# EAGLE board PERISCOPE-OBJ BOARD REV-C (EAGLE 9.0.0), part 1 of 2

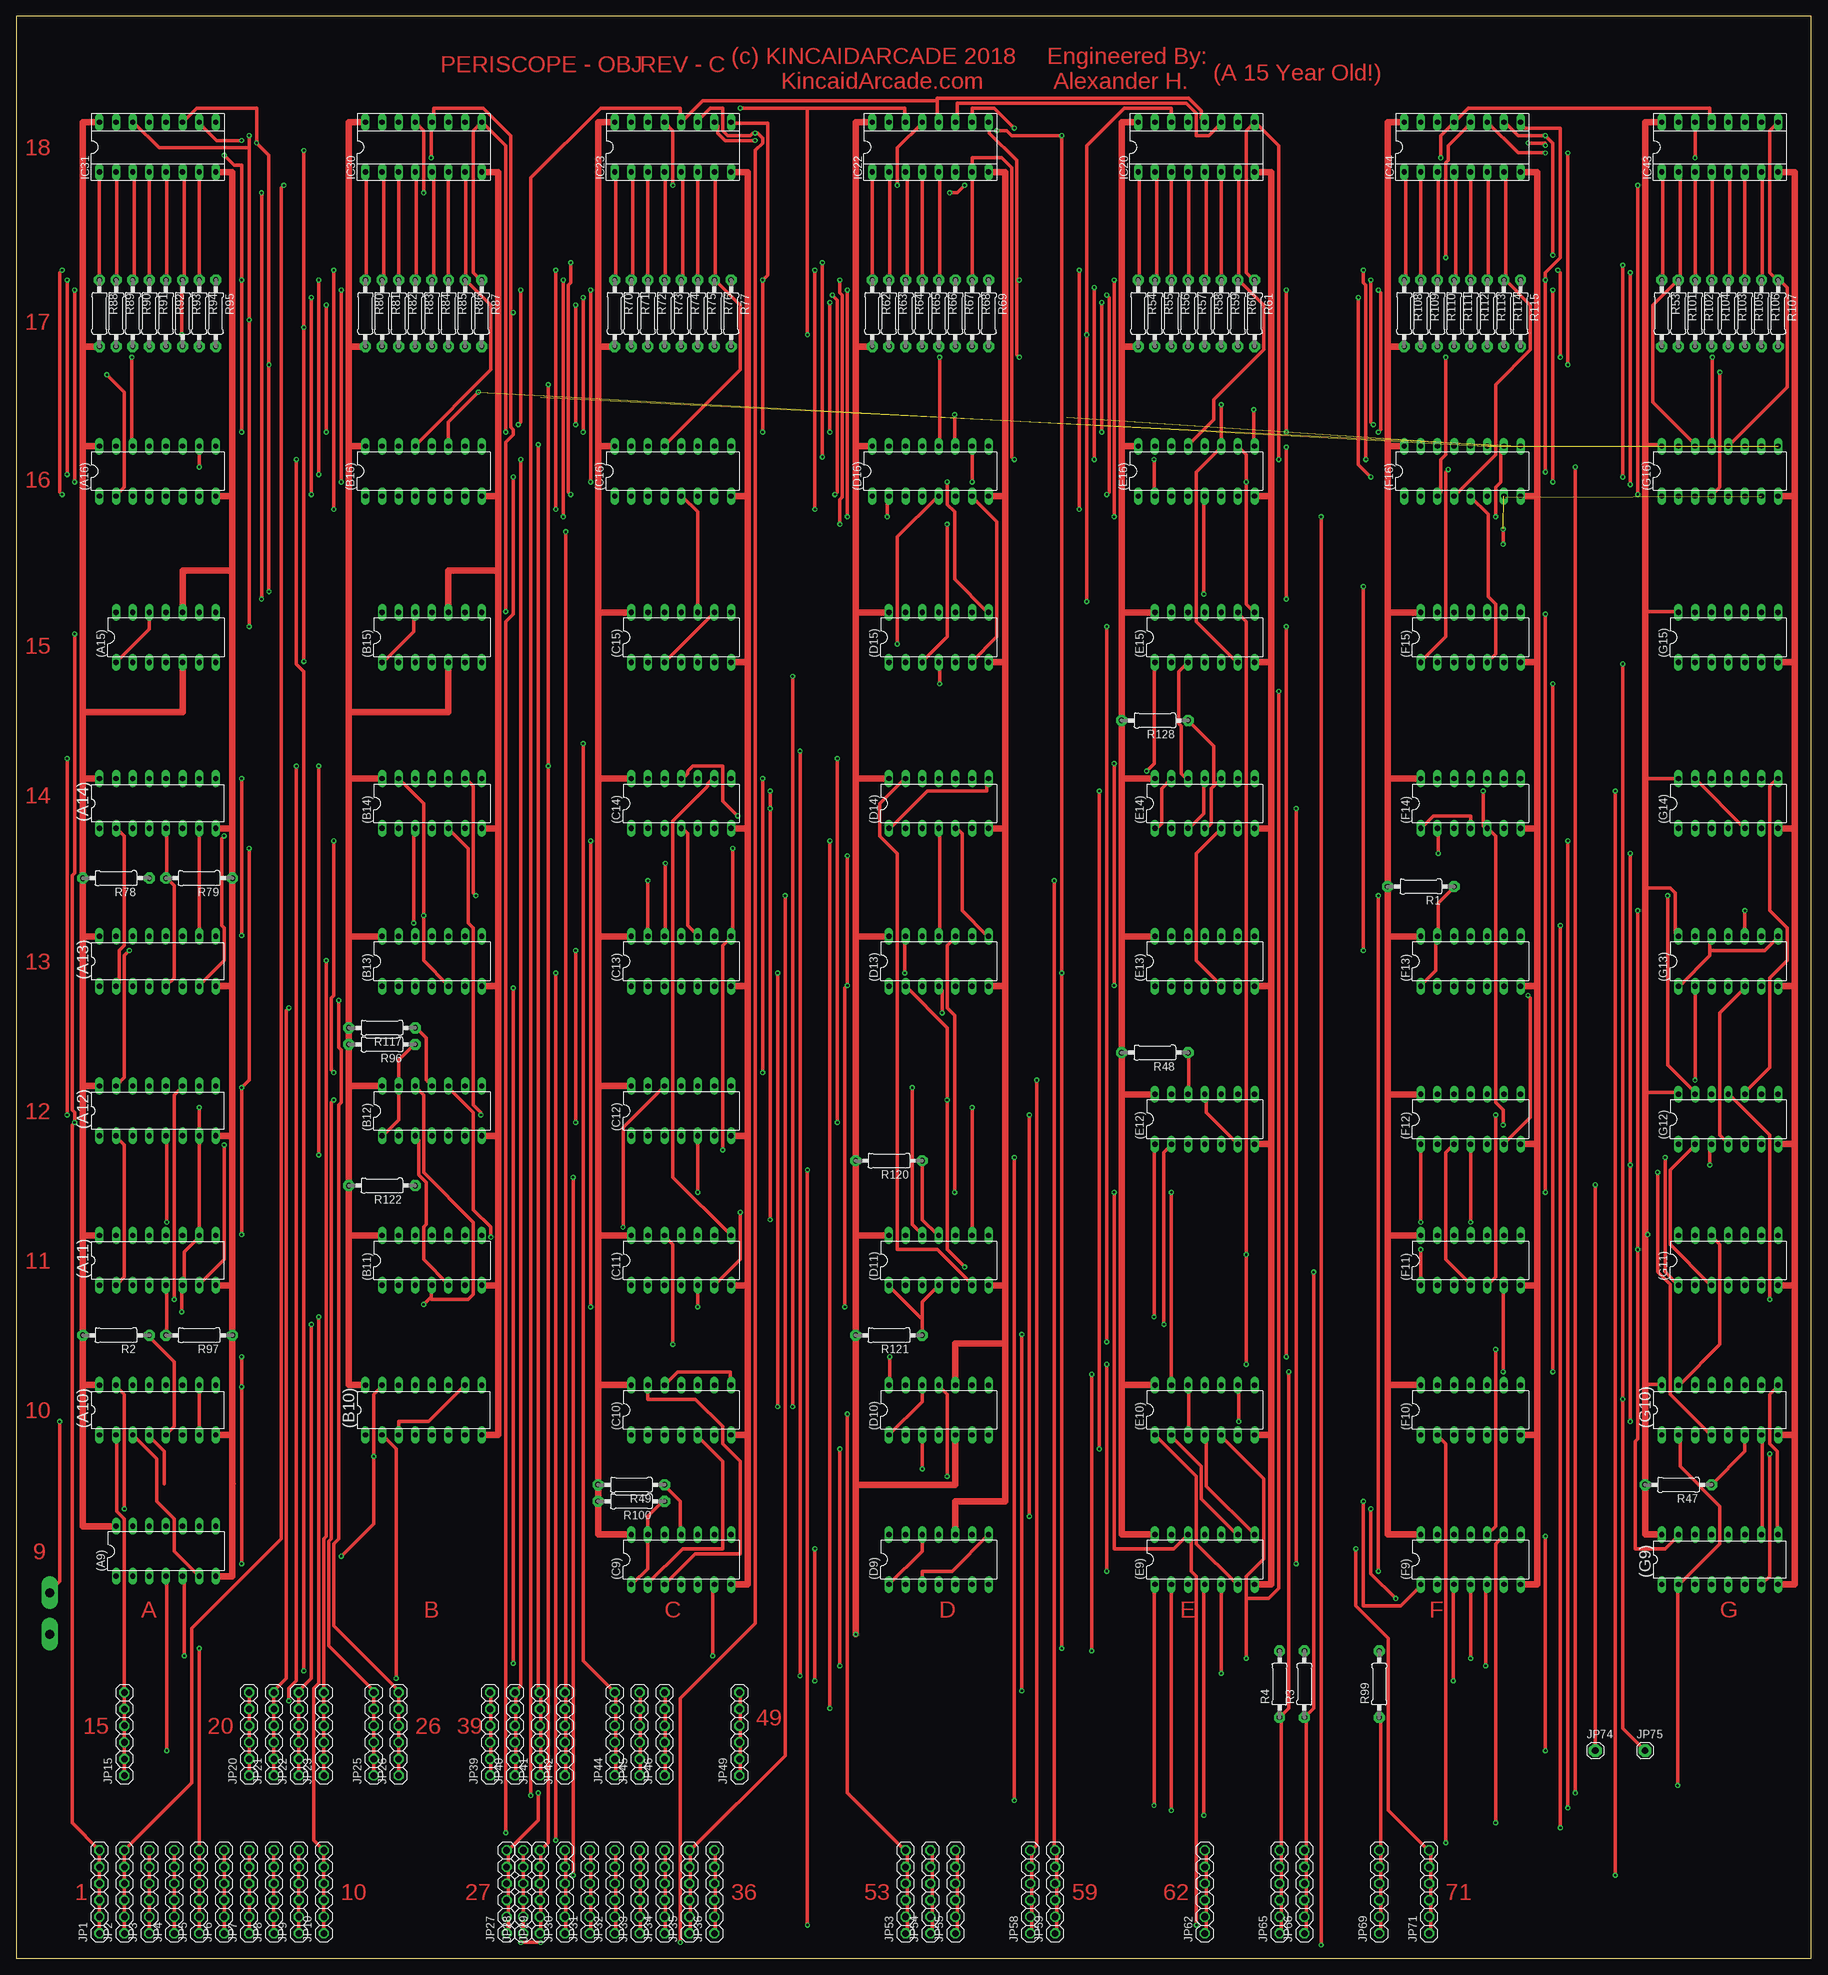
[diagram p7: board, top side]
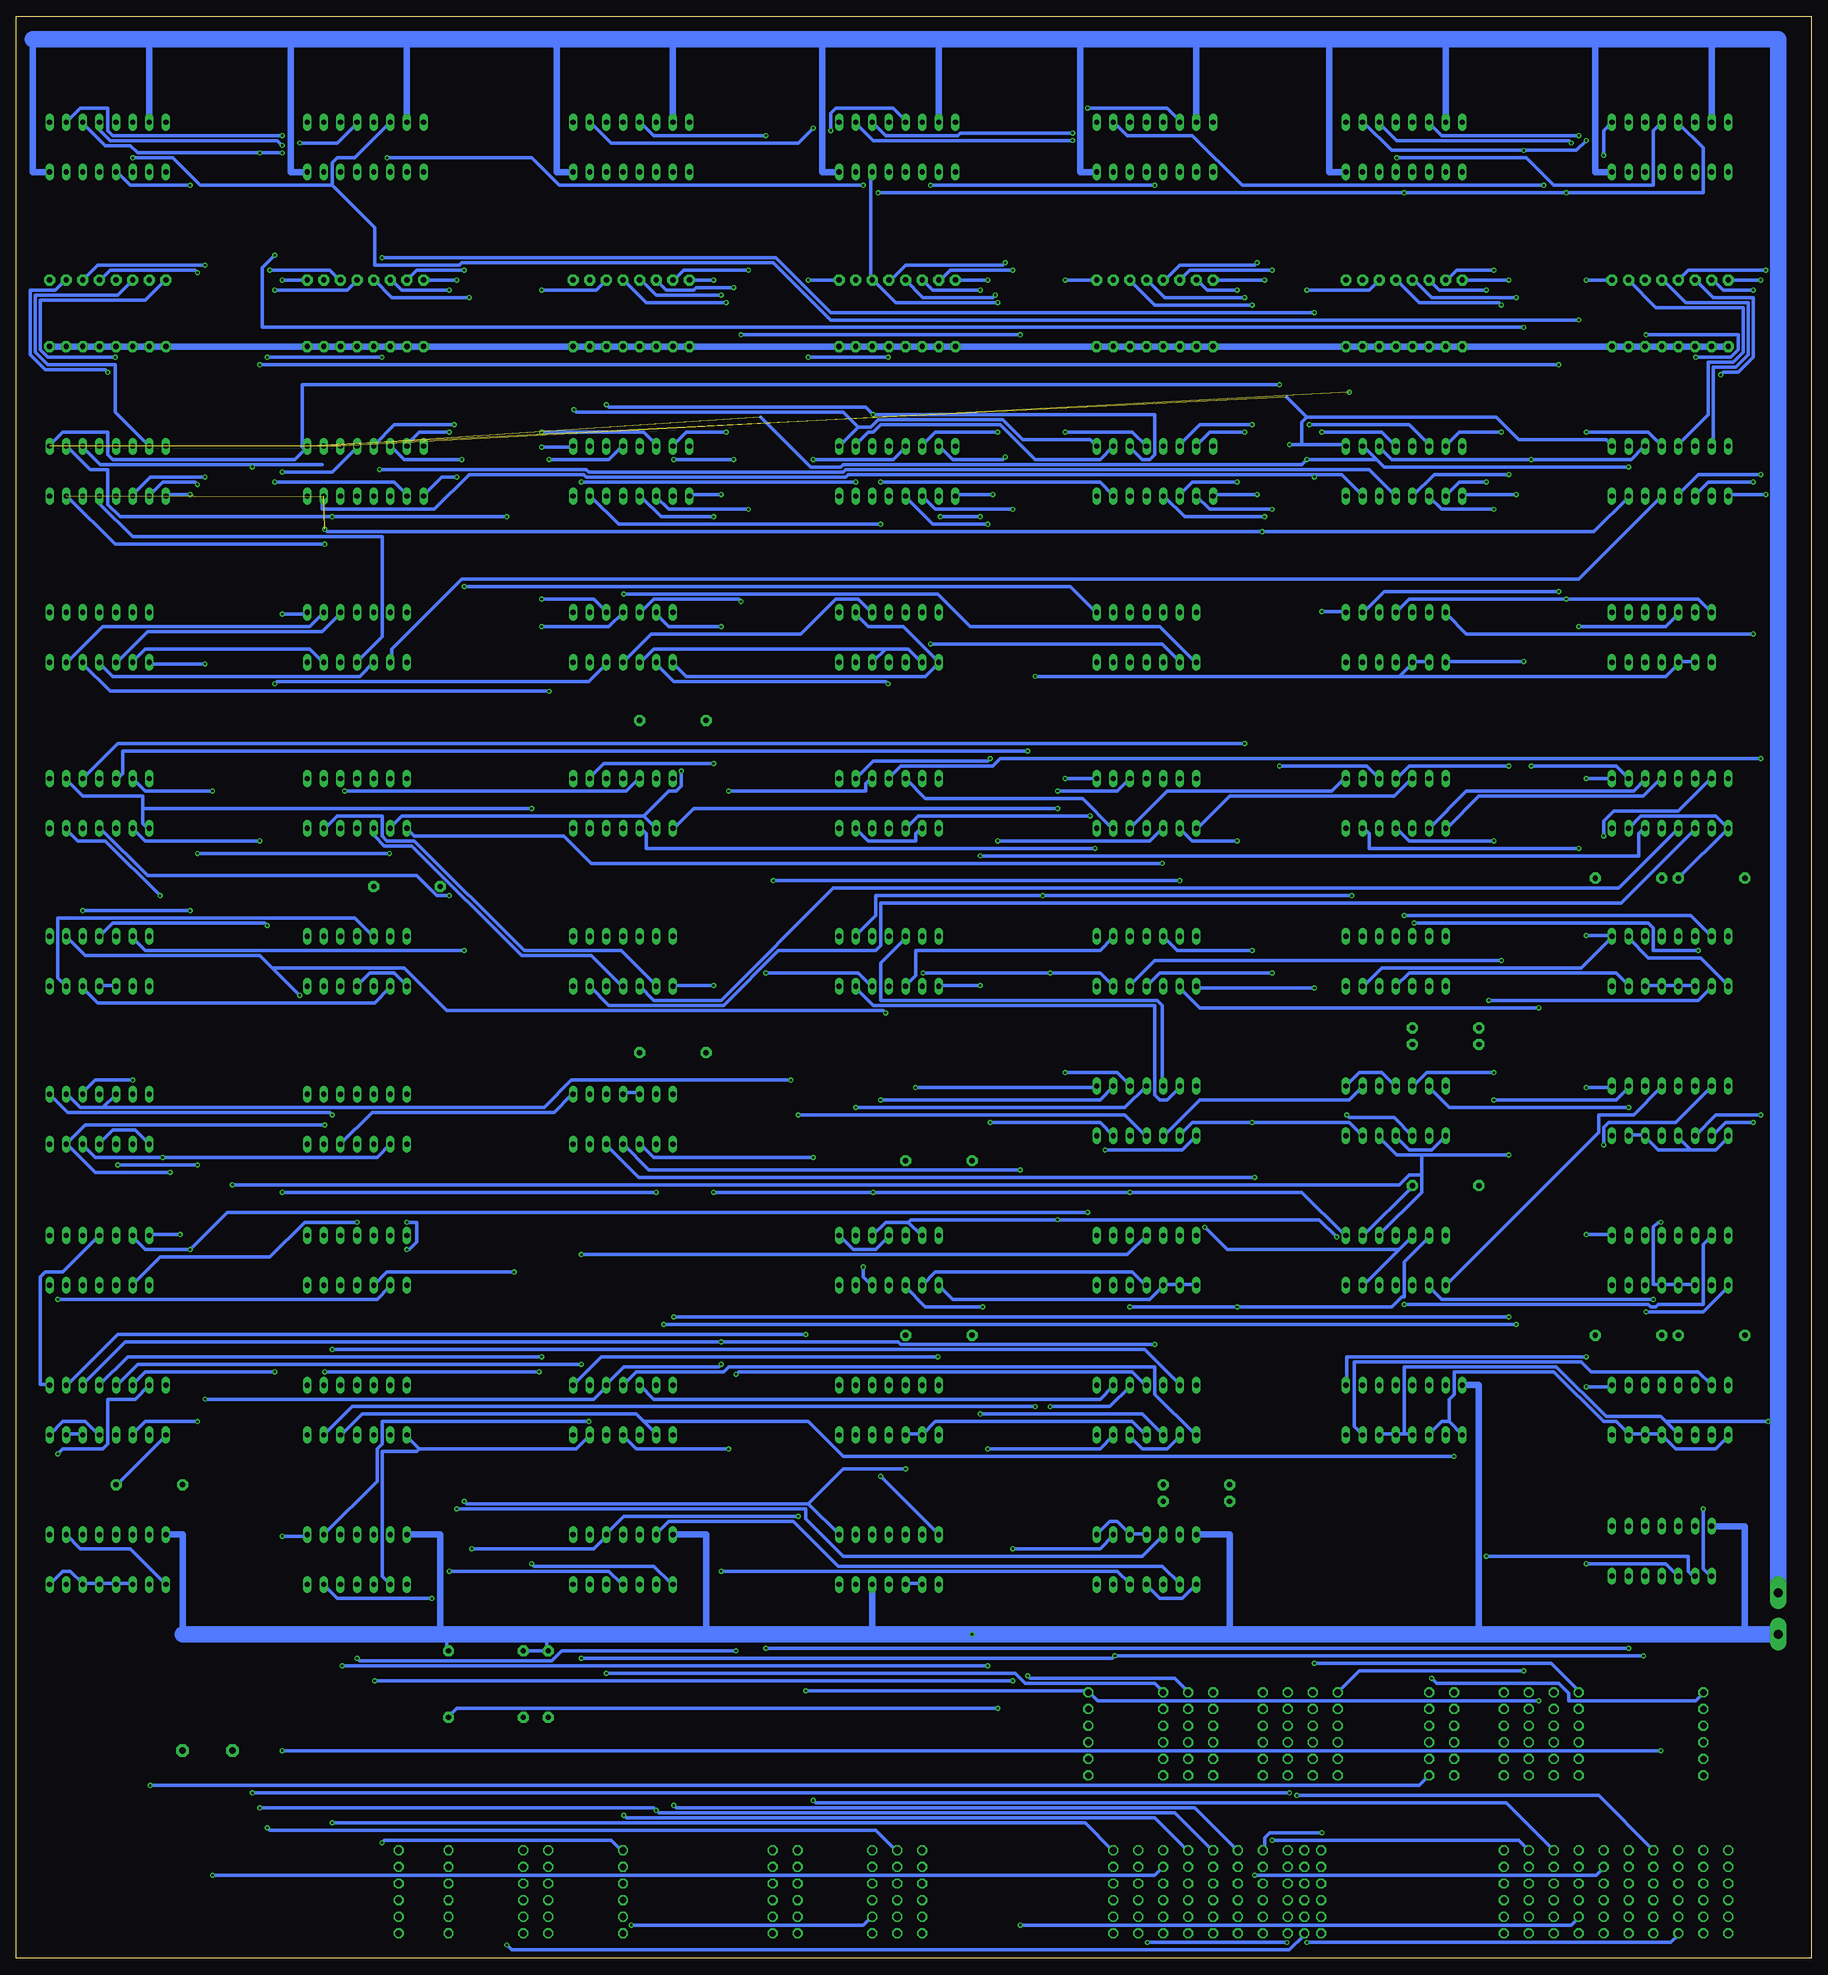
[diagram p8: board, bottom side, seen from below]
Size 274.3 x 296.85 mm. Coordinates in mm from the lower left corner, seen from the top.
Outline: 0,0 274.3,0 274.3,296.85 0,296.85 0,0
Copper layers (1*16): Top 0.035mm / dielectric 1.5mm / Bottom 0.035mm
Design rules "default": minimum track width 6mil, minimum drill 0.35mm, track to track 6mil, track to pad 6mil, pad to pad 6mil, via to via 6mil, smd to smd 6mil, copper to edge 40mil, drill to drill 6mil, minimum pad ring 10mil, minimum via ring 8mil, stop-mask expansion 4mil, vias tented up to drill 0mil, thermal gap 10mil
Net classes: 0 default: width 0.508 mm, clearance 0.254 mm

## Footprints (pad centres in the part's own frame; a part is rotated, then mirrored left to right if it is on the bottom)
DIL14 = drill 0.813 long: 1 -7.62,-3.81; 2 -5.08,-3.81; 3 -2.54,-3.81; 4 0,-3.81; 5 2.54,-3.81; 6 5.08,-3.81; 7 7.62,-3.81; 8 7.62,3.81; 9 5.08,3.81; 10 2.54,3.81; 11 0,3.81; 12 -2.54,3.81; 13 -5.08,3.81; 14 -7.62,3.81
DIL16 = drill 0.813 long: 1 -8.89,-3.81; 2 -6.35,-3.81; 3 -3.81,-3.81; 4 -1.27,-3.81; 5 1.27,-3.81; 6 3.81,-3.81; 7 6.35,-3.81; 8 8.89,-3.81; 9 8.89,3.81; 10 6.35,3.81; 11 3.81,3.81; 12 1.27,3.81; 13 -1.27,3.81; 14 -3.81,3.81; 15 -6.35,3.81; 16 -8.89,3.81
SOCKET-16 = drill 0.813 long: 1 -8.89,-3.81; 2 -6.35,-3.81; 3 -3.81,-3.81; 4 -1.27,-3.81; 5 1.27,-3.81; 6 3.81,-3.81; 7 6.35,-3.81; 8 8.89,-3.81; 9 8.89,3.81; 10 6.35,3.81; 11 3.81,3.81; 12 1.27,3.81; 13 -1.27,3.81; 14 -3.81,3.81; 15 -6.35,3.81; 16 -8.89,3.81
1X06 = drill 1.016 octagon: 1 -6.35,0; 2 -3.81,0; 3 -1.27,0; 4 1.27,0; 5 3.81,0; 6 6.35,0
1X1-BIGPOGO = drill 1.4 pad 2.54 long: P$1 0,0
1X01 = drill 1.016 pad 1.93 octagon: 1 0,0
0207/10 = drill 0.813 pad 1.676 octagon: 1 -5.08,0; 2 5.08,0

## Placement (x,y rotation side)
(A9)  7400N  [DIL14]  22.86,62.23 0 top
(A10)  74161N  [DIL16]  21.59,83.82 0 top
(A11)  74161N  [DIL16]  21.59,106.68 0 top
(A12)  74161N  [DIL16]  21.59,129.54 0 top
(A13)  74161N  [DIL16]  21.59,152.4 0 top
(A14)  74161N  [DIL16]  21.59,176.53 0 top
(A15)  74LS93N  [DIL14]  22.86,201.93 0 top
(A16)  74151N  [DIL16]  21.59,227.33 0 top
(B10)  74161N  [DIL16]  62.23,83.82 0 top
(B11)  74LS21N  [DIL14]  63.5,106.68 0 top
(B12)  74107N  [DIL14]  63.5,129.54 0 top
(B13)  7400N  [DIL14]  63.5,152.4 0 top
(B14)  7410N  [DIL14]  63.5,176.53 0 top
(B15)  74LS93N  [DIL14]  63.5,201.93 0 top
(B16)  74151N  [DIL16]  62.23,227.33 0 top
(C9)  74107N  [DIL14]  101.6,60.96 0 top
(C10)  74S08N  [DIL14]  101.6,83.82 0 top
(C11)  7430N  [DIL14]  101.6,106.68 0 top
(C12)  74S08N  [DIL14]  101.6,129.54 0 top
(C13)  74LS21N  [DIL14]  101.6,152.4 0 top
(C14)  7404N  [DIL14]  101.6,176.53 0 top
(C15)  7432N  [DIL14]  101.6,201.93 0 top
(C16)  74151N  [DIL16]  100.33,227.33 0 top
(D9)  74LS93N  [DIL14]  140.97,60.96 0 top
(D10)  74LS93N  [DIL14]  140.97,83.82 0 top
(D11)  74107N  [DIL14]  140.97,106.68 0 top
(D13)  74S08N  [DIL14]  140.97,152.4 0 top
(D14)  7432N  [DIL14]  140.97,176.53 0 top
(D15)  7400N  [DIL14]  140.97,201.93 0 top
(D16)  74151N  [DIL16]  139.7,227.33 0 top
(E9)  74LS21N  [DIL14]  181.61,60.96 0 top
(E10)  74S08N  [DIL14]  181.61,83.82 0 top
(E12)  7430N  [DIL14]  181.61,128.27 0 top
(E13)  7432N  [DIL14]  181.61,152.4 0 top
(E14)  74S74N  [DIL14]  181.61,176.53 0 top
(E15)  7404N  [DIL14]  181.61,201.93 0 top
(E16)  74151N  [DIL16]  180.34,227.33 0 top
(F9)  7432N  [DIL14]  222.25,60.96 0 top
(F10)  7404N  [DIL14]  222.25,83.82 0 top
(F11)  7402N  [DIL14]  222.25,106.68 0 top
(F12)  7404N  [DIL14]  222.25,128.27 0 top
(F13)  74107N  [DIL14]  222.25,152.4 0 top
(F14)  74S08N  [DIL14]  222.25,176.53 0 top
(F15)  7432N  [DIL14]  222.25,201.93 0 top
(F16)  74151N  [DIL16]  220.98,227.33 0 top
(G9)  74161N  [DIL16]  260.35,60.96 0 top
(G10)  74161N  [DIL16]  260.35,83.82 0 top
(G11)  7400N  [DIL14]  261.62,106.68 0 top
(G12)  7432N  [DIL14]  261.62,128.27 0 top
(G13)  74S08N  [DIL14]  261.62,152.4 0 top
(G14)  74LS21N  [DIL14]  261.62,176.53 0 top
(G15)  74S08N  [DIL14]  261.62,201.93 0 top
(G16)  74151N  [DIL16]  260.35,227.33 0 top
IC20  82S23 #5  [SOCKET-16]  180.34,276.86 0 top
IC22  82S23 #4  [SOCKET-16]  139.7,276.86 0 top
IC23  82S23 #3  [SOCKET-16]  100.33,276.86 0 top
IC30  82S23 #2  [SOCKET-16]  62.23,276.86 0 top
IC31  82S23 #1  [SOCKET-16]  21.59,276.86 0 top
IC43  82S23 #7  [SOCKET-16]  260.35,276.86 0 top
IC44  82S23 #6  [SOCKET-16]  220.98,276.86 0 top
JP1  [1X06]  12.7,10.16 90 top
JP2  [1X06]  16.51,10.16 90 top
JP3  [1X06]  20.32,10.16 90 top
JP4  [1X06]  24.13,10.16 90 top
JP5  [1X06]  27.94,10.16 90 top
JP6  [1X06]  31.75,10.16 90 top
JP7  [1X06]  35.56,10.16 90 top
JP8  [1X06]  39.37,10.16 90 top
JP9  [1X06]  43.18,10.16 90 top
JP10  [1X06]  46.99,10.16 90 top
JP15  [1X06]  16.51,34.29 90 top
JP20  [1X06]  35.56,34.29 90 top
JP21  [1X06]  39.37,34.29 90 top
JP22  [1X06]  43.18,34.29 90 top
JP23  [1X06]  46.99,34.29 90 top
JP25  [1X06]  54.61,34.29 90 top
JP26  [1X06]  58.42,34.29 90 top
JP27  [1X06]  74.93,10.16 90 top
JP28  [1X06]  77.47,10.16 90 top
JP29  [1X06]  80.01,10.16 90 top
JP30  [1X06]  83.82,10.16 90 top
JP31  [1X06]  87.63,10.16 90 top
JP32  [1X06]  91.44,10.16 90 top
JP33  [1X06]  95.25,10.16 90 top
JP34  [1X06]  99.06,10.16 90 top
JP35  [1X06]  102.87,10.16 90 top
JP36  [1X06]  106.68,10.16 90 top
JP39  [1X06]  72.39,34.29 90 top
JP40  [1X06]  76.2,34.29 90 top
JP41  [1X06]  80.01,34.29 90 top
JP42  [1X06]  83.82,34.29 90 top
JP44  [1X06]  91.44,34.29 90 top
JP45  [1X06]  95.25,34.29 90 top
JP46  [1X06]  99.06,34.29 90 top
JP49  [1X06]  110.49,34.29 90 top
JP53  [1X06]  135.89,10.16 90 top
JP54  [1X06]  139.7,10.16 90 top
JP55  [1X06]  143.51,10.16 90 top
JP58  [1X06]  154.94,10.16 90 top
JP59  [1X06]  158.75,10.16 90 top
JP62  [1X06]  181.61,10.16 90 top
JP65  [1X06]  193.04,10.16 90 top
JP66  [1X06]  196.85,10.16 90 top
JP69  [1X06]  208.28,10.16 90 top
JP71  [1X06]  215.9,10.16 90 top
JP72  [1X1-BIGPOGO]  5.08,49.53 90 top
JP73  [1X1-BIGPOGO]  5.08,55.88 90 top
JP74  [1X01]  241.3,31.75 0 top
JP75  [1X01]  248.92,31.75 0 top
R1  1K  [0207/10]  214.63,163.83 180 top
R2  1K  [0207/10]  15.24,95.25 180 top
R3  1K  [0207/10]  196.85,41.91 90 top
R4  1K  [0207/10]  193.04,41.91 90 top
R47  1K  [0207/10]  254,72.39 180 top
R48  1K  [0207/10]  173.99,138.43 180 top
R49  1K  [0207/10]  93.98,72.39 180 top
R53  1K  [0207/10]  251.46,251.46 270 top
R54  1K  [0207/10]  171.45,251.46 270 top
R55  1K  [0207/10]  173.99,251.46 270 top
R56  1K  [0207/10]  176.53,251.46 270 top
R57  1K  [0207/10]  179.07,251.46 270 top
R58  1K  [0207/10]  181.61,251.46 270 top
R59  1K  [0207/10]  184.15,251.46 270 top
R60  1K  [0207/10]  186.69,251.46 270 top
R61  1K  [0207/10]  189.23,251.46 270 top
R62  1K  [0207/10]  130.81,251.46 270 top
R63  1K  [0207/10]  133.35,251.46 270 top
R64  1K  [0207/10]  135.89,251.46 270 top
R65  1K  [0207/10]  138.43,251.46 270 top
R66  1K  [0207/10]  140.97,251.46 270 top
R67  1K  [0207/10]  143.51,251.46 270 top
R68  1K  [0207/10]  146.05,251.46 270 top
R69  1K  [0207/10]  148.59,251.46 270 top
R70  1K  [0207/10]  91.44,251.46 270 top
R71  1K  [0207/10]  93.98,251.46 270 top
R72  1K  [0207/10]  96.52,251.46 270 top
R73  1K  [0207/10]  99.06,251.46 270 top
R74  1K  [0207/10]  101.6,251.46 270 top
R75  1K  [0207/10]  104.14,251.46 270 top
R76  1K  [0207/10]  106.68,251.46 270 top
R77  1K  [0207/10]  109.22,251.46 270 top
R78  1K  [0207/10]  15.24,165.1 180 top
R79  1K  [0207/10]  27.94,165.1 180 top
R80  1K  [0207/10]  53.34,251.46 270 top
R81  1K  [0207/10]  55.88,251.46 270 top
R82  1K  [0207/10]  58.42,251.46 270 top
R83  1K  [0207/10]  60.96,251.46 270 top
R84  1K  [0207/10]  63.5,251.46 270 top
R85  1K  [0207/10]  66.04,251.46 270 top
R86  1K  [0207/10]  68.58,251.46 270 top
R87  1K  [0207/10]  71.12,251.46 270 top
R88  1K  [0207/10]  12.7,251.46 270 top
R89  1K  [0207/10]  15.24,251.46 270 top
R90  1K  [0207/10]  17.78,251.46 270 top
R91  1K  [0207/10]  20.32,251.46 270 top
R92  1K  [0207/10]  22.86,251.46 270 top
R93  1K  [0207/10]  25.4,251.46 270 top
R94  1K  [0207/10]  27.94,251.46 270 top
R95  1K  [0207/10]  30.48,251.46 270 top
R96  1K  [0207/10]  55.88,139.7 180 top
R97  1K  [0207/10]  27.94,95.25 180 top
R99  1K  [0207/10]  208.28,41.91 90 top
R100  1K  [0207/10]  93.98,69.85 180 top
R101  1K  [0207/10]  254,251.46 270 top
R102  1K  [0207/10]  256.54,251.46 270 top
R103  1K  [0207/10]  261.62,251.46 270 top
R104  1K  [0207/10]  259.08,251.46 270 top
R105  1K  [0207/10]  264.16,251.46 270 top
R106  1K  [0207/10]  266.7,251.46 270 top
R107  1K  [0207/10]  269.24,251.46 270 top
R108  1K  [0207/10]  212.09,251.46 270 top
R109  1K  [0207/10]  214.63,251.46 270 top
R110  1K  [0207/10]  217.17,251.46 270 top
R111  1K  [0207/10]  219.71,251.46 270 top
R112  1K  [0207/10]  222.25,251.46 270 top
R113  1K  [0207/10]  224.79,251.46 270 top
R114  1K  [0207/10]  227.33,251.46 270 top
R115  1K  [0207/10]  229.87,251.46 270 top
R117  1K  [0207/10]  55.88,142.24 180 top
R120  1K  [0207/10]  133.35,121.92 180 top
R121  1K  [0207/10]  133.35,95.25 180 top
R122  1K  [0207/10]  55.88,118.11 180 top
R128  1K  [0207/10]  173.99,189.23 180 top

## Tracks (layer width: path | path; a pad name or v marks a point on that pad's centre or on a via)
1H  (via drill 0.35)
  Top 0.508: JP2.1 JP2.2 JP2.3 JP2.4 JP2.5 JP2.6 26.8,26.8 26.8,50.42 40.51,64.13 40.51,270.64 v40.89,271.02 | IC23.10 107.19,280.16 107.19,279.02 108.33,277.88 v112.9,277.88 | v152.53,279.78 149.48,282.83 146.05,282.83 IC22.10
  Bottom 0.508: v112.9,277.88 143.38,277.88 146.05,280.54 IC22.10 | v152.53,279.78 154.81,277.5 183.39,277.5 186.44,280.54 IC20.10 | v40.89,271.02 87,271.02 94.62,278.64 104.52,278.64 106.43,280.54 IC23.10
1V  (via drill 0.35)
  Top 0.508: JP27.1 75.18,3.94 75.18,6.22 JP27.2 75.18,6.6 75.18,8.89 | 75.18,8.89 75.18,11.18 JP27.4 75.18,11.56 75.18,13.84 JP27.5 75.18,14.22 75.18,16.51 | 75.18,8.89 JP27.3 | v238.25,25.27 v238.25,227.97 | v79.76,25.27 79.76,21.08 75.18,16.51 | 75.18,16.51 JP27.6
  Bottom 0.508: 238.25,228.35 261.49,228.35 264.16,231.01 | 238.25,228.35 227.58,228.35 | v238.25,227.97 238.25,228.35 | v79.76,25.27 v238.25,25.27
2H  (via drill 0.35)
  Top 0.508: JP3.1 JP3.2 JP3.3 JP3.4 JP3.5 JP3.6 | IC23.11 104.14,280.92 106.05,282.83 107.95,282.83 107.95,279.4 108.71,278.64 112.14,278.64 112.52,279.02 v112.9,279.02 113.28,279.02 114.05,278.26 114.05,277.5 112.9,276.35 112.9,51.18 101.47,39.75 v101.47,2.41 | IC20.11 184.15,280.54 182.25,278.64 180.34,278.64 180.34,282.07 178.82,283.59 143.76,283.59 143.76,280.92 IC22.11 | v80.14,2.41 v77.09,2.41
  Bottom 0.508: v112.9,279.02 130.05,279.02 130.43,278.64 141.48,278.64 IC22.11 | JP3.1 20.32,3.56 21.46,2.41 v77.09,2.41 | v101.47,2.41 v80.14,2.41
2V  (via drill 0.35)
  Top 0.508: 226.82,230.63 226.82,225.68 226.06,224.92 v226.06,220.34 | JP28.6 JP28.5 JP28.4 JP28.3 JP28.2 JP28.1 | v199.39,2.03 v199.39,220.34
  Bottom 0.508: 266.45,231.01 263.02,227.58 260.35,227.58 260.35,222.25 258.44,220.34 v226.06,220.34 v199.39,220.34 | v199.39,2.03 198.63,1.27 79.76,1.27 77.47,3.56 JP28.1
4H  (via drill 0.35)
  Top 0.508: JP4.1 JP4.2 JP4.3 JP4.4 JP4.5 JP4.6 | 140.72,283.97 104.9,283.97 IC23.12 101.47,280.92 101.47,282.83 89.28,282.83 78.61,272.16 v78.61,24.89 | 140.72,283.97 140.72,280.92 IC22.12 | 140.72,283.97 140.72,284.35 179.2,284.35 181.1,282.45 181.1,281.31 181.48,280.92 IC20.12
  Bottom 0.508: JP4.6 32.51,24.89 v78.61,24.89
4V  (via drill 0.35)
  Top 0.508: JP29.1 80.14,3.94 80.14,6.22 JP29.2 80.14,6.6 80.14,8.89 | 80.14,8.89 80.14,11.18 JP29.4 80.14,11.56 80.14,13.84 JP29.5 80.14,14.22 80.14,16.51 | 80.14,8.89 JP29.3 | 80.14,16.51 81.28,17.65 v81.28,182.25 v81.28,240.54 | 80.14,16.51 JP29.6
  Bottom 0.508: (B14).10 67.95,182.25 v81.28,182.25 | 230.25,230.63 231.78,229.11 259.59,229.11 260.35,229.87 260.35,233.3 267.21,233.3 269.11,231.39 | 230.25,230.63 229.87,231.01 | 230.25,230.63 230.63,231.01 230.63,240.54 v81.28,240.54
8H  (via drill 0.35)
  Top 0.508: IC23.13 100.33,279.4 v100.33,271.02 | v134.62,271.02 134.62,276.73 138.43,280.54 IC22.13 | JP5.1 JP5.2 JP5.3 JP5.4 JP5.5 JP5.6 v27.94,47.37 | v159.77,47.37 v159.77,150.62 v159.77,278.64 152.15,278.64 151.38,279.4 v149.86,279.4
  Bottom 0.508: v134.62,271.02 v100.33,271.02 | v159.77,150.62 145.67,150.62 143.76,148.72 (D13).5 | v159.77,278.64 176.91,278.64 178.82,280.54 IC20.13 | v159.77,47.37 v27.94,47.37 | v149.86,279.4 149.86,282.07 149.1,282.83 140.34,282.83 138.43,280.92 IC22.13
8V  (via drill 0.35)  (1 unrouted)
  Top 0.508: JP30.1 83.95,3.94 83.95,6.22 JP30.2 83.95,6.6 83.95,8.89 | 83.95,8.89 83.95,11.18 JP30.4 83.95,11.56 83.95,13.84 JP30.5 83.95,14.22 83.95,16.51 JP30.6 | 83.95,8.89 JP30.3 | v75.95,226.44 75.95,205.49 74.8,204.34 v74.8,19.18
  Bottom 0.508: 75.95,226.82 147.19,226.82 147.57,226.44 187.2,226.44 187.58,226.82 205.11,226.82 210.44,221.49 227.58,221.49 227.58,223.39 | 75.95,226.82 71.76,226.82 68.71,223.77 (B16).7 | 75.95,226.82 v75.95,226.44 | v74.8,19.18 82.8,19.18 83.57,18.41 83.57,16.51 JP30.6
16H  (via drill 0.35)
  Top 0.508: JP6.1 JP6.2 JP6.3 JP6.4 JP6.5 JP6.6 | v85.09,12.7 v85.09,119.38
  Bottom 0.508: v85.09,119.38 179.2,119.38 184.15,124.33 (E12).5 | v85.09,12.7 32.89,12.7 31.75,13.84 JP6.5
16V  (via drill 0.35)
  Top 0.508: JP31.1 87.76,3.94 87.76,6.22 JP31.2 87.76,6.6 87.76,8.89 | 87.76,8.89 87.76,11.18 JP31.4 87.76,11.56 87.76,13.84 JP31.5 87.76,14.22 87.76,16.51 JP31.6 | 87.76,8.89 JP31.3 | v173.86,23.37 173.86,56.9 (E9).1 | v195.58,60.33 v195.58,175.77
  Bottom 0.508: 255.02,175.77 255.02,177.67 264.16,177.67 266.83,180.34 (G14).9 | 255.02,175.77 255.02,173.48 254.25,172.72 (G14).1 | v173.86,23.37 173.48,22.99 94.23,22.99 87.76,16.51 JP31.6 | v195.58,175.77 255.02,175.77 | v195.58,60.33 195.2,59.94 176.91,59.94 174.24,57.28 (E9).1
32H  (via drill 0.35)
  Top 0.508: JP7.6 JP7.5 JP7.4 JP7.3 JP7.2 JP7.1 | v120.9,5.08 v120.9,120.52
  Bottom 0.508: (E12).4 177.67,120.52 v120.9,120.52 | v120.9,5.08 36.7,5.08 35.56,6.22 JP7.2
32V  (via drill 0.35)
  Top 0.508: JP32.1 91.57,3.94 91.57,6.22 JP32.2 91.57,6.6 91.57,8.89 | 91.57,8.89 91.57,11.18 JP32.4 91.57,11.56 91.57,13.84 JP32.5 91.57,14.22 91.57,16.51 JP32.6 | 91.57,8.89 JP32.3 | v176.53,22.61 (E9).2 | v237.11,22.99 v237.11,170.81
  Bottom 0.508: JP32.6 91.57,16.51 97.28,22.23 176.15,22.23 v176.53,22.61 176.91,22.99 v237.11,22.99 | (G14).2 254.64,170.81 v237.11,170.81
64H  (via drill 0.35)
  Top 0.508: JP8.1 JP8.2 JP8.3 JP8.4 JP8.5 JP8.6 | v152.53,24.13 v152.53,122.43
  Bottom 0.508: v152.53,122.43 176.91,122.43 178.82,124.33 (E12).3 | v152.53,24.13 152.15,23.75 46.61,23.75 JP8.6
64V  (via drill 0.35)
  Top 0.508: JP33.1 95.38,3.94 95.38,6.22 JP33.2 95.38,6.6 95.38,8.89 | 95.38,8.89 95.38,11.18 JP33.4 95.38,11.56 95.38,13.84 JP33.5 95.38,14.22 95.38,16.51 JP33.6 | 95.38,8.89 JP33.3 | v181.48,21.84 181.48,56.9 (E9).4 | v208.15,59.18 v208.15,162.43
  Bottom 0.508: v181.48,21.84 181.1,21.46 100.33,21.46 95.38,16.51 JP33.6 | v208.15,162.43 210.06,162.43 213.11,165.48 254.25,165.48 261.49,172.72 (G14).4 | v208.15,59.18 183.77,59.18 181.86,57.28 (E9).4
128H  (via drill 0.35)
  Top 0.508: JP9.1 JP9.2 JP9.3 JP9.4 JP9.5 JP9.6 | v82.42,18.03 v82.42,150.62
  Bottom 0.508: (C13).4 99.57,150.62 v82.42,150.62 | v82.42,18.03 44.7,18.03 JP9.6
128V  (via drill 0.35)
  Top 0.508: JP34.1 99.19,3.94 99.19,6.22 JP34.2 99.19,6.6 99.19,8.89 | 99.19,8.89 99.19,11.18 JP34.4 99.19,11.56 99.19,13.84 JP34.5 99.19,14.22 99.19,16.51 JP34.6 | 99.19,8.89 JP34.3 | (G14).13 (G14).5 | v244.35,178.44 v244.35,12.7
  Bottom 0.508: JP34.5 100.33,12.7 v244.35,12.7 | v244.35,178.44 254.64,178.44 (G14).13
256H  (via drill 0.35)
  Top 0.508: JP10.1 JP10.2 JP10.3 JP10.4 JP10.5 JP10.6 45.47,18.03 45.47,41.27 46.23,42.04 v46.23,98.04 | v173.86,98.04 173.86,124.33 (E12).1
  Bottom 0.508: v46.23,98.04 v173.86,98.04
256V  (via drill 0.35)
  Top 0.508: JP35.1 103,3.94 103,6.22 JP35.2 103,6.6 103,8.89 | 103,8.89 103,11.18 JP35.4 103,11.56 103,13.84 JP35.5 103,14.22 103,16.51 | 103,8.89 JP35.3 | v70.23,162.43 69.85,162.81 69.85,179.2 68.71,180.34 (B14).9 | 103,16.51 117.48,30.99 v117.48,162.43 | 103,16.51 JP35.6
  Bottom 0.508: v70.23,162.43 v117.48,162.43 143,162.43 143,159.38 146.05,156.34 (D13).9
/1H  (via drill 0.35)
  Top 0.508: JP15.1 JP15.2 JP15.3 JP15.4 JP15.5 JP15.6 16.51,67.18 15.37,68.33 15.37,79.76 (A10).2 | (B10).2 58.04,77.85 v58.04,42.8
  Bottom 0.508: v58.04,42.8 57.28,42.04 38.61,42.04 37.08,40.51 37.08,39.37 17.65,39.37 16.51,40.51 JP15.6
/1V  (via drill 0.35)  (2 unrouted)
  Top 0.508: JP39.1 72.52,27.94 72.52,30.23 JP39.2 72.52,30.61 72.52,32.89 JP39.3 72.52,33.27 72.52,35.56 | 72.52,35.56 72.52,37.85 JP39.5 72.52,38.23 72.52,40.51 JP39.6 | 72.52,35.56 JP39.4 | v43.94,43.94 43.94,196.72 42.8,197.87 v42.8,229.11 | v70.61,239.4 66.04,234.82 (B16).11
  Bottom 0.508: (A16).11 25.65,231.01 27.56,229.11 v42.8,229.11 64.14,229.11 66.04,231.01 (B16).11 | JP39.6 69.09,43.94 v43.94,43.94
/2V  (via drill 0.35)  (2 unrouted)
  Top 0.508: JP40.1 76.33,27.94 76.33,30.23 JP40.2 76.33,30.61 76.33,32.89 JP40.3 76.33,33.27 76.33,35.56 | 76.33,35.56 76.33,37.85 JP40.5 76.33,38.23 76.33,40.51 JP40.6 76.33,40.89 77.09,41.66 v77.09,229.11 | 76.33,35.56 JP40.4 | v27.94,227.97 (A16).10
  Bottom 0.508: v27.94,227.97 65.28,227.97 66.42,229.11 | 66.42,229.11 68.33,231.01 (B16).10 | 66.42,229.11 v77.09,229.11 77.85,228.35 147.96,228.35 148.34,227.97 152.91,227.97 160.53,235.59
/4V  (via drill 0.35)  (2 unrouted)
  Top 0.508: JP41.1 80.14,27.94 80.14,30.23 JP41.2 80.14,30.61 80.14,32.89 JP41.3 80.14,33.27 80.14,35.56 | 80.14,35.56 80.14,37.85 JP41.5 80.14,38.23 80.14,40.51 JP41.6 79.76,40.89 v79.76,231.39 | 80.14,35.56 JP41.4
  Bottom 0.508: 77.09,235.59 48.13,235.59 44.7,232.16 31.37,232.16 30.61,231.39 (A16).9 | 77.09,235.59 77.85,234.82 77.85,231.39 | 77.85,231.39 71.37,231.39 (B16).9 | 77.85,231.39 v79.76,231.39 | 77.09,235.59 80.14,238.63
/8V  (via drill 0.35)  (1 unrouted)
  Top 0.508: JP42.1 83.95,27.94 83.95,30.23 JP42.2 83.95,30.61 83.95,32.89 JP42.3 83.95,33.27 83.95,35.56 | 83.95,35.56 83.95,37.85 JP42.5 83.95,38.23 83.95,40.51 JP42.6 83.95,40.89 v83.95,218.06 | 83.95,35.56 JP42.4 | v227.2,218.44 v227.2,216.15
  Bottom 0.508: v227.2,218.44 226.82,218.06 v83.95,218.06 33.27,218.06 27.94,223.39 (A16).7 | 266.45,223.39 259.21,216.15 v227.2,216.15
/32H  (via drill 0.35)
  Top 0.508: JP20.1 JP20.2 JP20.3 JP20.4 JP20.5 JP20.6 | v75.95,45.09 v75.95,148.34
  Bottom 0.508: v75.95,148.34 93.85,148.34 (C13).1 | v75.95,45.09 39.75,45.09 35.56,40.89 JP20.6
/32V  (via drill 0.35)
  Top 0.508: 91.57,35.56 91.57,37.85 JP44.5 91.57,38.23 91.57,40.51 JP44.6 86.61,45.47 v86.61,185.67 | JP44.1 91.57,27.94 91.57,30.23 JP44.2 91.57,30.61 91.57,32.89 JP44.3 91.57,33.27 91.57,35.56 | 91.57,35.56 JP44.4
  Bottom 0.508: (G14).10 258.83,185.67 v86.61,185.67
/64H  (via drill 0.35)
  Top 0.508: JP21.1 JP21.2 JP21.3 JP21.4 JP21.5 JP21.6 39.37,40.89 41.27,42.8 41.27,144.91 v41.66,145.29
  Bottom 0.508: v41.66,145.29 93.47,145.29 96.52,148.34 (C13).2
/64V  (via drill 0.35)
  Top 0.508: 95.38,35.56 95.38,37.85 JP45.5 95.38,38.23 95.38,40.51 JP45.6 | JP45.1 95.38,27.94 95.38,30.23 JP45.2 95.38,30.61 95.38,32.89 JP45.3 95.38,33.27 95.38,35.56 | 95.38,35.56 JP45.4 | v119.76,43.18 v119.76,184.53
  Bottom 0.508: v119.76,184.53 258.06,184.53 258.06,181.1 258.83,180.34 (G14).12 | v119.76,43.18 119.38,42.8 97.28,42.8 95.38,40.89 JP45.6
/128H  (via drill 0.35)
  Top 0.508: JP22.1 JP22.2 JP22.3 JP22.4 JP22.5 JP22.6 43.18,40.89 45.09,42.8 v45.09,96.9 | v175.39,96.9 175.39,123.19 176.53,124.33 (E12).2
  Bottom 0.508: v45.09,96.9 v175.39,96.9
/128V  (via drill 0.35)
  Top 0.508: 99.19,35.56 99.19,37.85 JP46.5 99.19,38.23 99.19,40.51 JP46.6 | JP46.1 99.19,27.94 99.19,30.23 JP46.2 99.19,30.61 99.19,32.89 JP46.3 99.19,33.27 99.19,35.56 | 99.19,35.56 JP46.4 | v184.15,43.56 (E9).5
  Bottom 0.508: v184.15,43.56 121.67,43.56 120.14,42.04 100.33,42.04 99.19,40.89 JP46.6
/256H  (via drill 0.35)
  Top 0.508: JP23.1 JP23.2 JP23.3 JP23.4 JP23.5 JP23.6 46.99,64.13 47.37,64.52 v47.37,152.53
  Bottom 0.508: v47.37,152.53 100.33,152.53 104.14,148.72 (C13).5
/ACTIVEEXPLOSION  (via drill 0.35)
  Top 0.508: v25.65,46.23 25.65,58.42 (A9).5 | v106.43,46.23 106.43,56.9 (C9).6 | v187.96,45.85 187.96,54.99 | 187.96,54.99 187.96,58.42 190.63,61.09 190.63,73.28 184.15,79.76 (E10).5 | v192.91,193.68 192.91,56.52 191.39,54.99 187.96,54.99
  Bottom 0.508: v25.65,46.23 v106.43,46.23 106.81,45.85 v187.96,45.85 | v192.91,193.68 259.97,193.68 264.16,197.87 (G15).5
/FREIGHTERHEN  (via drill 0.35)
  Top 0.508: v118.62,195.96 v118.62,84.33
  Bottom 0.508: (A15).2 18.03,198.25 20.32,198.25 (A15).3 20.32,197.87 22.23,195.96 62.99,195.96 | (B15).2 58.42,198.25 60.71,198.25 (B15).3 61.09,197.87 62.99,195.96 | (F10).6 223.01,84.33 v118.62,84.33 | 62.99,195.96 v118.62,195.96
/GAME  (via drill 0.35)
  Top 0.508: JP59.1 159,3.94 159,6.22 JP59.2 159,6.6 159,8.89 | 159,8.89 159,11.18 JP59.4 159,11.56 159,13.84 JP59.5 159,14.22 159,16.51 JP59.6 158.62,16.51 v158.62,164.72 | 159,8.89 JP59.3 | v96.52,164.72 (C13).13
  Bottom 0.508: v158.62,164.72 v96.52,164.72
/HBLANK  (via drill 0.35)
  Top 0.508: JP25.1 JP25.2 JP25.3 JP25.4 JP25.5 JP25.6 54.61,40.89 47.75,47.75 47.75,63.75 48.13,64.13 48.13,130.81 v48.51,131.19
  Bottom 0.508: v48.51,131.19 29.84,131.19 27.94,133.1 (A12).10
/HITS  (via drill 0.35)
  Top 0.508: (E14).13 175.01,178.82 175.01,173.48 174.24,172.72 (E14).1 | v72.52,110.24 72.52,111.76 69.85,114.43 69.85,129.29 66.04,133.1 (B12).10 | v115.19,112.9 v115.19,175.77 v115.19,178.44
  Bottom 0.508: 138.05,112.52 136.14,110.62 (D11).13 | 138.05,112.52 141.48,112.52 (D11).10 | v72.52,110.24 75.18,112.9 v115.19,112.9 137.67,112.9 138.05,112.52 | (C14).10 106.05,178.44 v115.19,178.44 | v115.19,175.77 170.81,175.77 173.86,172.72 (E14).1
/HSYNC  (via drill 0.35)
  Top 0.508: (G10).2 254.25,79.76 254.25,75.18 260.35,69.09 260.35,63.37 254.25,57.28 (G9).2 253.87,56.9 v253.87,26.42 | JP26.1 JP26.2 JP26.3 JP26.4 JP26.5 JP26.6 58.42,40.89 48.51,50.8 48.51,63.37 49.28,64.13 49.28,130.43 49.66,130.81 49.66,138.81 49.28,139.19 v49.28,146.43 | (A13).2 15.75,149.1 15.75,154.05 16.51,154.81 16.51,171.58 15.37,172.72 (A14).2
  Bottom 0.508: v49.28,146.43 17.27,146.43 15.37,148.34 (A13).2 | v253.87,26.42 59.94,26.42 JP26.1
/MOVEDOWN  (via drill 0.35)
  Top 0.508: v114.05,180.34 v114.05,135.38
  Bottom 0.508: v114.05,135.38 106.05,135.38 104.14,133.48 (C12).10 | (C14).8 v114.05,180.34
/REPOSSUB
  Top 0.508: (G12).4 261.49,124.71 260.35,125.86 260.35,144.53 264.16,148.34 (G13).5
  Bottom 0.508: (G12).1 256.16,126.62 259.59,126.62 261.49,124.71 (G12).4 | (F13).2 217.3,148.34 219.58,146.05 261.87,146.05 264.16,148.34 (G13).5
/SQA  (via drill 0.35)
  Top 0.508: (E15).6 186.44,198.25 180.34,204.34 180.34,227.2 184.15,231.01 (E16).11 v184.15,237.49 | v143.38,235.97 143.38,231.39 (D16).11
  Bottom 0.508: (C16).11 104.14,231.01 102.23,229.11 101.09,229.11 100.33,229.87 100.33,235.97 v143.38,235.97 144.53,237.11 183.77,237.11 v184.15,237.49
/SQB  (via drill 0.35)
  Top 0.508: (E15).8 187.96,207.01 v187.96,225.68 187.96,229.87 (E16).10 | (D16).10 v146.05,225.68
  Bottom 0.508: (C16).10 108.71,229.11 118.62,229.11 123.95,234.44 142.24,234.44 143.38,233.3 144.15,233.3 146.05,231.39 (D16).10 | v146.05,225.68 v187.96,225.68
/SQC  (via drill 0.35)
  Top 0.508: v194.06,231.01 v194.06,207.77 | v189.1,236.73 189.1,231.39 (E16).9
  Bottom 0.508: v194.06,207.77 186.06,207.77 184.15,205.87 (E15).10 | v194.06,231.01 189.48,231.01 (E16).9 | (C16).9 110.24,232.16 120.52,232.16 123.57,235.2 142.62,235.2 143.76,234.06 145.67,234.06 | (D16).9 145.67,234.06 | v189.1,236.73 188.72,236.35 147.96,236.35 145.67,234.06
/SQD  (via drill 0.35)
  Top 0.508: 120.9,282.83 135.76,282.83 135.76,280.92 IC22.14 | 120.9,282.83 v110.62,282.83 | v163.58,207.39 v163.58,248.16 163.58,277.11 169.29,282.83 176.53,282.83 IC20.14 | v120.9,248.16 120.9,282.83
  Bottom 0.508: v110.62,282.83 98.43,282.83 96.52,280.92 IC23.14 | v163.58,207.39 163.96,207.77 176.91,207.77 178.82,205.87 (E15).12 | v163.58,248.16 v120.9,248.16
/VBLANK  (via drill 0.35)
  Top 0.508: 110.62,35.56 110.62,37.85 JP49.5 110.62,38.23 110.62,40.51 JP49.6 | JP49.1 110.62,27.94 110.62,30.23 JP49.2 110.62,30.61 110.62,32.89 JP49.3 110.62,33.27 110.62,35.56 | 110.62,35.56 JP49.4 | v42.8,182.25 42.8,42.42 41.66,41.27 v41.66,39.37 | v153.67,40.89 v153.67,95.38
  Bottom 0.508: (A14).10 29.84,182.25 v42.8,182.25 | v41.66,39.37 109.09,39.37 110.24,40.51 JP49.6 110.62,40.89 v153.67,40.89 | v153.67,95.38 258.83,95.38 266.45,87.76 (G10).10
A
  Top 0.508: (A10).3 21.46,76.33 21.46,69.85 24.13,67.18 24.13,62.23 (A9).6
ACTIVEEXPLOSION  (via drill 0.35)
  Top 0.508: v166.62,90.81 v166.62,59.18 | v245.49,197.87 v245.49,85.47 245.49,35.18 JP75.1
  Bottom 0.508: v166.62,59.18 106.05,59.18 104.14,57.28 (C9).5 | v166.62,90.81 167,90.42 181.48,90.42 184.15,87.76 (E10).10 184.15,87.38 186.06,85.47 v245.49,85.47 | v245.49,197.87 253.87,197.87 (G15).1
ADDPOINT  (via drill 0.35)
  Top 0.508: JP62.1 181.86,3.94 181.86,6.22 JP62.2 181.86,6.6 181.86,8.89 | 181.86,8.89 181.86,11.18 JP62.4 181.86,11.56 181.86,13.84 JP62.5 181.86,14.22 181.86,16.51 JP62.6 | 181.86,8.89 JP62.3 | v218.44,17.65 218.44,78.61 217.3,79.76 (F10).2
  Bottom 0.508: v218.44,17.65 218.06,18.03 183.39,18.03 181.86,16.51 JP62.6
BB  (via drill 0.35)
  Top 0.508: (G11).1 251.97,104.9 v251.97,122.43
  Bottom 0.508: (G12).5 264.16,124.33 262.25,122.43 v251.97,122.43 219.2,122.43 (F12).2
CENTERED
  Bottom 0.508: (D13).3 138.43,148.72 136.91,150.24 136.91,154.05 108.71,154.05 106.81,155.96 (C13).9
CLK  (via drill 0.35)
  Top 0.508: JP1.1 JP1.2 JP1.3 JP1.4 JP1.5 JP1.6 8.51,20.7 8.51,127.38 v8.89,127.76 8.89,129.29 8.51,129.67 8.51,165.48 8.89,165.86 v8.89,202.44 | (A11).2 16.51,104.14 16.51,124.33 15.37,125.48 (A12).2
  Bottom 0.508: v8.89,202.44 52.7,202.44 55.75,205.49 (B15).14 | v8.89,127.76 13.08,127.76 14.99,125.86 (A12).2
CONDITION1  (via drill 0.35)
  Top 0.508: v165.48,77.85 v165.48,178.44 | (E9).8 181.86,72.14 181.86,79.76 (E10).4
  Bottom 0.508: v165.48,178.44 144.53,178.44 144.53,179.58 143.76,180.34 (D14).10 | v165.48,77.85 179.58,77.85 181.48,79.76 (E10).4
DFREIGHTER
  Bottom 0.508: (E10).11 179.58,89.66 166.24,89.66 165.48,90.42 100.33,90.42 100.33,86.23 94.23,80.14 (C10).1
DOWN  (via drill 0.35)
  Top 0.508: v142.24,225.68 142.24,222.25 143.38,221.11 143.38,210.82 148.34,205.87 (D15).8
  Bottom 0.508: v142.24,225.68 108.71,225.68 106.81,223.77 (C16).7
ENDEXPLOSION  (via drill 0.35)
  Top 0.508: (D9).8 143,59.18 138.43,59.18 (D9).3 | v205.87,69.85 205.87,53.85 211.58,53.85 214.63,56.9 (F9).1 | v138.43,74.8 (D10).3
  Bottom 0.508: (C10).4 101.85,80.14 103.76,82.04 133.86,82.04 (D10).2 136.14,80.14 138.43,80.14 (D10).3 | (D9).2 136.14,57.28 138.43,57.28 (D9).3 | v205.87,69.85 205.49,69.47 153.29,69.47 | (D9).8 153.29,69.47 | v138.43,74.8 147.96,74.8 153.29,69.47
FIRE  (via drill 0.35)
  Top 0.508: JP69.1 208.53,3.94 208.53,6.22 JP69.2 208.53,6.6 208.53,8.89 | 208.53,8.89 208.53,11.18 JP69.4 208.53,11.56 208.53,13.84 JP69.5 208.53,14.22 208.53,16.51 | 208.53,8.89 JP69.3 | v124.33,38.23 v124.33,170.81 | 208.53,16.51 208.53,36.7 R99.1 | 208.53,16.51 JP69.6
  Bottom 0.508: v124.33,170.81 101.09,170.81 99.19,172.72 (C14).3 | v124.33,38.23 207.01,38.23 208.15,37.08 R99.1
FQA  (via drill 0.35)
  Top 0.508: IC44.10 227.58,280.54 229.49,278.64 v233.68,278.64 234.82,277.5 v234.82,260.35 | (B15).1 56.13,198.25 60.71,202.82 60.71,205.49 (B15).12 | v34.42,277.88 30.61,277.88 27.94,280.54 IC31.10 | v43.94,276.35 v43.94,249.3 v43.94,198.25
  Bottom 0.508: v233.68,278.64 259.59,278.64 260.35,279.4 260.35,282.83 264.54,282.83 IC43.10 | v34.42,277.88 35.94,276.35 v43.94,276.35 64.14,276.35 68.33,280.54 IC30.10 | v43.94,198.25 55.75,198.25 (B15).1 | v234.82,260.35 236.73,258.44 236.73,249.3 v43.94,249.3
FQB  (via drill 0.35)
  Top 0.508: IC44.11 229.49,275.97 v233.68,275.97 | IC31.11 27.56,282.83 36.7,282.83 v36.7,277.5 38.61,275.59 v38.61,243.59 v38.61,208.92 | v237.11,243.59 v237.11,275.97
  Bottom 0.508: v233.68,275.97 v237.11,275.97 255.78,275.97 256.92,277.11 260.73,277.11 264.16,280.54 IC43.11 | v36.7,277.5 37.08,277.88 63.37,277.88 66.04,280.54 IC30.11 | v38.61,208.92 65.28,208.92 68.33,205.87 (B15).9 | v38.61,243.59 v237.11,243.59
FQC  (via drill 0.35)
  Top 0.508: v231.01,277.5 233.68,277.5 v233.68,277.11 | v63.37,275.21 63.37,280.54 IC30.12 63.75,280.92 63.75,282.83 71.37,282.83 75.57,278.64 75.57,251.59 | v74.8,205.87 74.8,231.78 75.95,232.92 75.95,233.68 75.57,234.06 75.57,251.59 | v218.44,259.97 218.44,274.45 218.82,274.83 218.82,277.11 222.25,280.54 IC44.12 | 75.57,251.59 v75.95,251.59
  Bottom 0.508: v231.01,277.5 225.3,277.5 222.25,280.54 IC44.12 | v233.68,277.11 234.44,277.88 259.97,277.88 261.49,279.4 261.49,280.54 IC43.12 | IC31.12 24.13,279.4 24.13,271.02 39.37,271.02 43.56,275.21 v63.37,275.21 | v74.8,205.87 71.37,205.87 (B15).8 | v218.44,259.97 158.24,259.97 149.86,251.59 v75.95,251.59
FQD  (via drill 0.35)
  Top 0.508: IC43.13 258.83,280.92 258.83,282.83 221.87,282.83 IC44.13 217.68,278.64 v217.68,275.21 | v62.23,269.88 62.23,279.4 IC30.13 | v144.91,271.02 143.76,269.88 v142.62,269.88 | v37.46,269.88 v37.46,207.77
  Bottom 0.508: (A15).14 17.27,207.77 v37.46,207.77 61.47,207.77 (B15).11 | IC31.13 20.32,280.54 16.51,276.73 16.51,269.88 v37.46,269.88 v62.23,269.88 v142.62,269.88 | v217.68,275.21 195.58,275.21 191.39,271.02 v144.91,271.02
FQE  (via drill 0.35)
  Top 0.508: IC43.14 v256.54,275.21 | (A15).1 20.32,203.2 (A15).12 | 35.56,276.73 21.84,276.73 18.03,280.54 IC31.14 | v35.56,278.64 35.56,276.73 | 35.56,276.73 v35.56,250.44 v35.56,203.58
  Bottom 0.508: IC44.14 222.63,275.21 225.3,275.21 226.06,274.45 226.06,271.02 | 226.06,271.02 246.25,271.02 250.44,275.21 v256.54,275.21 | v35.56,278.64 56.52,278.64 58.42,280.54 IC30.14 | v35.56,203.58 22.23,203.58 20.32,205.49 (A15).12 | 226.06,271.02 219.58,264.54 219.58,258.83 206.63,258.83 206.25,259.21 158.62,259.21 149.86,250.44 v35.56,250.44
FREIGHTER  (via drill 0.35)
  Top 0.508: JP53.1 136.14,3.94 136.14,6.22 JP53.2 136.14,6.6 136.14,8.89 | 136.14,8.89 136.14,11.18 JP53.4 136.14,11.56 136.14,13.84 JP53.5 136.14,14.22 136.14,16.51 JP53.6 135.76,16.51 127,25.27 v127,83.19 | 136.14,8.89 JP53.3
  Bottom 0.508: (C10).3 102.23,83.19 v127,83.19
FREIGHTEREN
  Top 0.508: (E10).3 179.2,80.14 179.2,87.38 (E10).12
  Bottom 0.508: (E10).12 176.91,85.47 108.71,85.47 106.81,87.38 (C10).9
FREIGHTERHEN  (via drill 0.35)
  Top 0.508: (E10).2 176.53,79.76 181.1,75.18 181.1,70.23 186.44,64.9 (E9).9 | v49.66,61.47 54.61,66.42 v54.61,76.71 54.61,86.23 55.75,87.38 (B10).15
  Bottom 0.508: 178.44,82.04 176.53,80.14 (E10).2 | 178.44,82.04 179.58,83.19 221.49,83.19 224.54,80.14 (F10).5 | v49.66,61.47 18.8,61.47 18.8,59.18 18.03,58.42 (A9).2 | 178.44,82.04 153.29,82.04 147.96,76.71 v54.61,76.71
FREIGHTERPROMDATA  (via drill 0.35)
  Top 0.508: v176.53,117.09 (E10).13 | v233.68,205.49 v233.68,117.09
  Bottom 0.508: v233.68,117.09 v176.53,117.09 | v233.68,205.49 229.87,205.49 (F15).8
FREIGHTERVEN
  Top 0.508: (E10).1 180.34,73.66 180.34,63.37 186.44,57.28 (E9).6
GAME  (via drill 0.35)
  Top 0.508: JP58.1 155.19,3.94 155.19,6.22 JP58.2 155.19,6.6 155.19,8.89 | 155.19,8.89 155.19,11.18 JP58.4 155.19,11.56 155.19,13.84 JP58.5 155.19,14.22 155.19,16.51 | 155.19,8.89 JP58.3 | v155.96,134.24 155.96,17.27 155.19,16.51 | 155.19,16.51 JP58.6
  Bottom 0.508: 261.11,130.05 (G12).12 | 261.11,130.05 264.54,130.05 266.45,131.95 (G12).9 | 261.11,130.05 193.68,130.05 189.48,134.24 v155.96,134.24
GND  (via drill 0.35)
  Top 0.508: 33.27,72.52 33.02,72.52 | R97.1 33.27,95.38 33.02,95.38 | 33.27,165.1 R79.1 | 22.61,72.52 22.61,77.47 20.32,79.76 (A10).4 | v6.6,82.04 6.6,57.66 5.08,56.13 JP73.P$1
  Top 1.016: IC31.8 33.02,273.05 33.02,223.52 | 33.02,223.52 33.02,212.09 | 33.02,212.09 33.02,172.72 | 33.02,172.72 R79.1 33.02,148.59 | 33.02,148.59 33.02,125.73 | 33.02,125.73 33.02,102.87 | 33.02,102.87 33.02,95.38 R97.1 33.02,80.01 | 33.02,80.01 33.02,72.52 33.02,58.42 (A9).7 | (A10).8 33.02,80.01 | (A11).8 33.02,102.87 | (A12).8 33.02,125.73 | (A13).8 33.02,148.59 | (A14).8 33.02,172.72 | (A15).10 25.4,212.09 33.02,212.09 | (A16).8 33.02,223.52 | IC30.8 73.66,273.05 73.66,223.52 | 73.66,223.52 73.66,212.09 | 73.66,212.09 73.66,172.72 | 73.66,172.72 73.66,148.59 | 73.66,148.59 73.66,125.73 | 73.66,125.73 73.66,102.87 | 73.66,102.87 73.66,80.01 (B10).8 | (B11).7 73.66,102.87 | (B12).7 73.66,125.73 | (B13).7 73.66,148.59 | (B14).7 73.66,172.72 | (B15).10 66.04,212.09 73.66,212.09 | (B16).8 73.66,223.52 | IC23.8 111.76,273.05 111.76,223.52 | 111.76,223.52 111.76,198.12 | 111.76,198.12 111.76,172.72 | 111.76,172.72 111.76,148.59 | 111.76,148.59 111.76,125.73 | 111.76,125.73 111.76,102.87 | 111.76,102.87 111.76,80.01 | 111.76,80.01 111.76,57.15 (C9).7 | (C10).7 111.76,80.01 | (C11).7 111.76,102.87 | (C12).7 111.76,125.73 | (C13).7 111.76,148.59 | (C14).7 111.76,172.72 | (C15).7 111.76,198.12 | (C16).8 111.76,223.52 | IC22.8 151.13,273.05 151.13,223.52 | 151.13,223.52 151.13,198.12 | 151.13,198.12 151.13,172.72 | 151.13,172.72 151.13,148.59 | 151.13,148.59 151.13,102.87 | 151.13,102.87 151.13,93.98 | 151.13,93.98 151.13,69.85 143.51,69.85 (D9).10 | (D10).10 143.51,93.98 151.13,93.98 | (D11).7 151.13,102.87 | (D13).7 151.13,148.59 | (D14).7 151.13,172.72 | (D15).7 151.13,198.12 | (D16).8 151.13,223.52 | IC20.8 191.77,273.05 191.77,223.52 | 191.77,223.52 191.77,198.12
  Top 1.016: 191.77,198.12 191.77,172.72 | 191.77,172.72 191.77,148.59 | 191.77,148.59 191.77,124.46 | 191.77,124.46 191.77,80.01 | 191.77,80.01 191.77,57.15 (E9).7 | (E10).7 191.77,80.01 | (E12).7 191.77,124.46 | (E13).7 191.77,148.59 | (E14).7 191.77,172.72 | (E15).7 191.77,198.12 | (E16).8 191.77,223.52 | IC44.8 232.41,273.05 232.41,223.52 | 232.41,223.52 232.41,198.12 | 232.41,198.12 232.41,172.72 | 232.41,172.72 232.41,148.59 | 232.41,148.59 232.41,124.46 | 232.41,124.46 232.41,102.87 | 232.41,102.87 232.41,80.01 | 232.41,80.01 232.41,57.15 (F9).7 | (F10).7 232.41,80.01 | (F11).7 232.41,102.87 | (F12).7 232.41,124.46 | (F13).7 232.41,148.59 | (F14).7 232.41,172.72 | (F15).7 232.41,198.12 | (F16).8 232.41,223.52 | IC43.8 271.78,273.05 271.78,223.52 | 271.78,223.52 271.78,198.12 | 271.78,198.12 271.78,172.72 | 271.78,172.72 271.78,148.59 | 271.78,148.59 271.78,124.46 | 271.78,124.46 271.78,102.87 | 271.78,102.87 271.78,80.01 | 271.78,80.01 271.78,57.15 (G9).8 | (G10).8 271.78,80.01 | (G11).7 271.78,102.87 | (G12).7 271.78,124.46 | (G13).7 271.78,148.59 | (G14).7 271.78,172.72 | (G15).7 271.78,198.12 | (G16).8 271.78,223.52
  Bottom 0.508: (G9).3 256.54,57.28 258.83,57.28 (G9).4 259.21,57.28 261.49,57.28 (G9).5 261.87,57.28 264.16,57.28 | (G10).8 267.21,82.04 263.78,82.04 261.87,80.14 (G10).5 | 264.16,57.28 266.06,59.18 267.21,59.18 (G9).8 | 264.16,57.28 (G9).6 | 62.23,80.14 63.37,80.14 (B10).5 63.75,80.14 66.04,80.14 (B10).6 | 62.23,80.14 61.09,80.14 (B10).4 | 62.23,80.14 62.23,90.42 38.99,90.42 31.37,82.8 22.99,82.8 22.23,82.04 | 22.23,82.04 20.32,80.14 (A10).4 | 22.23,82.04 v6.6,82.04
  Bottom 1.016: 33.02,293.37 33.02,273.05 IC31.8 | 73.66,293.37 73.66,273.05 IC30.8 | 111.76,293.37 111.76,273.05 IC23.8 | 151.13,293.37 151.13,273.05 IC22.8 | 193.04,293.37 191.77,292.1 191.77,273.05 IC20.8 | 232.41,293.37 232.41,273.05 IC44.8 | 271.78,293.37 271.78,273.05 IC43.8 | IC30.15 55.88,293.37 | IC23.15 93.98,293.37 | IC22.15 133.35,293.37 | IC20.15 173.99,293.37 | IC44.15 214.63,293.37 | IC43.15 254,293.37 | 13.97,293.37 15.24,292.1 IC31.15
  Bottom 2.54: JP73.P$1 5.08,293.37 13.97,293.37 33.02,293.37 55.88,293.37 73.66,293.37 93.98,293.37 111.76,293.37 133.35,293.37 151.13,293.37 173.99,293.37 193.04,293.37 214.63,293.37 232.41,293.37 254,293.37 271.78,293.37
HITS  (via drill 0.35)
  Top 0.508: v110.24,174.62 107.95,176.91 107.95,182.25 103.38,182.25 102.62,181.48 102.62,181.1 101.85,180.34 (C14).11
  Bottom 0.508: v110.24,174.62 136.53,174.62 (D14).3
INVISIBLE  (via drill 0.35)
  Top 0.508: (C9).3 103.76,61.85 110.62,61.85 110.62,75.95 107.95,78.61 107.95,81.28 103.76,85.47 96.52,85.47 (C10).13 | (F9).10 226.06,66.04 v226.06,93.09
  Bottom 0.508: v226.06,93.09 101.85,93.09 96.52,87.76 (C10).13
INVISIBLETORPEDO  (via drill 0.35)
  Top 0.508: (F14).1 216.53,174.62 222.25,174.62 (F14).4 | v85.47,127.76 v85.47,154.05 | v99.19,167.39 99.19,156.34 (C13).12
  Bottom 0.508: (B12).6 70.61,127.76 v85.47,127.76 94.62,127.76 96.52,125.86 (C12).2 | (C13).12 96.9,154.05 v85.47,154.05 | (F14).1 213.49,171.58 190.63,171.58 186.44,167.39 v99.19,167.39
JOYDOWN  (via drill 0.35)
  Top 0.508: JP66.1 197.1,3.94 197.1,6.22 JP66.2 197.1,6.6 197.1,8.89 | 197.1,8.89 197.1,11.18 JP66.4 197.1,11.56 197.1,13.84 JP66.5 197.1,14.22 197.1,16.51 | 197.1,8.89 JP66.3 | v198.25,104.9 198.25,38.23 R3.1 197.1,36.7 197.1,16.51 | 197.1,16.51 JP66.6
  Bottom 0.508: (F11).3 217.68,104.9 v198.25,104.9
JOYUP  (via drill 0.35)
  Top 0.508: JP65.1 193.29,3.94 193.29,6.22 JP65.2 193.29,6.6 193.29,8.89 | 193.29,8.89 193.29,11.18 JP65.4 193.29,11.56 193.29,13.84 JP65.5 193.29,14.22 193.29,16.51 | 193.29,8.89 JP65.3 | v227.2,89.66 227.2,102.62 (F11).6 | v194.44,89.66 194.44,38.23 R4.1 193.29,36.7 193.29,16.51 | 193.29,16.51 JP65.6
  Bottom 0.508: v194.44,89.66 v227.2,89.66
JUSTSHOT  (via drill 0.35)
  Top 0.508: (E14).3 179.2,172.72 181.48,175.01 181.48,180.34 (E14).11 | v107.95,123.57 107.95,154.81 109.09,155.96 (C13).8 109.47,156.34 v109.47,169.67
  Bottom 0.508: (C12).1 96.14,123.57 v107.95,123.57 | v109.47,169.67 178.05,169.67 178.05,171.96 178.82,172.72 (E14).3
LEVEL
  Top 0.508: (D15).6 146.05,198.25 149.86,202.06 149.86,219.58 146.05,223.39 (D16).7
MOVEDOWN
  Top 0.508: (C11).8 100.33,119.38 100.33,173.86 105.66,179.2 105.66,179.58 106.43,180.34 (C14).9
MOVETORPEDOH
  Top 0.508: (D11).6 146.05,103 140.72,108.33 134.62,108.33 134.62,168.91 131.95,171.58 131.95,176.53 135.76,180.34 (D14).13
N$1  (via drill 0.35)
  Top 0.508: v214.63,108.33 (F11).1 | (F12).1 v214.63,112.52
  Bottom 0.508: v214.63,108.33 214.25,108.33 213.11,109.47 213.11,112.52 v214.63,112.52
N$3
  Top 0.508: (F12).3 218.44,123.19 218.44,106.81 222.25,103 (F11).4
N$9  (via drill 0.35)
  Top 0.508: (F12).4 v222.25,112.52
  Bottom 0.508: v222.25,112.52 230.25,112.52 235.59,107.19 252.35,107.19 256.54,103 (G11).2
N$48
  Bottom 0.508: (F12).5 219.96,129.29 192.15,129.29 189.48,131.95 (E12).8
N$49  (via drill 0.35)
  Top 0.508: v136.91,133.1 136.91,112.14 138.43,110.62 (D11).12
  Bottom 0.508: v136.91,133.1 109.47,133.1 (C12).8
N$50
  Top 0.508: (G9).10 266.83,64.9 266.83,79.76 (G10).7 | R47.1 264.16,77.47 (G10).6
  Bottom 0.508: (G10).6 264.16,80.14 266.45,80.14 (G10).7 | (G9).1 256.92,62.61 264.54,62.61 (G9).10 | (G10).1 251.59,79.76 258.83,72.52 R47.1
N$51
  Top 0.508: (G9).9 269.11,64.9 269.11,77.47 267.97,78.61 267.97,86.23 269.11,87.38 (G10).9
  Bottom 0.508: (G11).11 267.21,104.9 269.88,104.9 270.64,104.14 270.64,87.76 269.49,87.76 (G10).9
N$52
  Top 0.508: (E12).6 181.86,129.29 181.86,131.95 (E12).11 | R48.1 179.2,138.43 179.2,132.33 (E12).12
  Bottom 0.508: (E12).12 179.2,132.33 181.48,132.33 (E12).11
N$53
  Top 0.508: (F13).1 214.63,148.72 216.92,151 216.92,155.96 (F13).13 217.3,156.34 217.3,161.29 219.58,163.58 R1.1
  Bottom 0.508: (F13).4 222.25,148.72 220.34,150.62 216.53,150.62 214.63,148.72 (F13).1
N$54
  Bottom 0.508: (G13).3 259.21,148.72 261.49,148.72 (G13).4
N$55
  Bottom 0.508: (G13).6 267.97,149.86 267.97,159 222.63,159 219.96,156.34 (F13).12
N$57
  Top 0.508: (B10).10 62.99,82.04 58.42,82.04 (B10).3 | (A10).7 (A10).10 | (A10).5 24.13,81.28 24.13,91.19 20.32,95 R2.1
  Bottom 0.508: 55.37,82.04 (B10).1 | 55.37,82.04 56.52,82.04 58.42,80.14 (B10).3 | 27.94,80.14 25.65,80.14 (A10).6 25.27,80.14 22.99,80.14 (A10).5 20.7,77.85 14.6,77.85 12.7,79.76 (A10).1 | 55.37,82.04 55.37,85.47 54.61,86.23 54.61,89.66 39.37,89.66 31.75,82.04 29.84,82.04 27.94,80.14 | 27.94,80.14 (A10).7
N$58
  Bottom 0.508: (F15).3 221.87,195.96 259.59,195.96 261.49,197.87 (G15).4
N$59
  Top 0.508: (D10).1 138.43,85.09 (D10).12
N$60  (via drill 0.35)
  Top 0.508: v34.42,60.33 v34.42,87.38 v34.42,91.95
  Bottom 0.508: (A9).3 22.23,60.33 v34.42,60.33 | v34.42,87.38 30.61,87.38 (A10).9 | v34.42,91.95 70.99,91.95 70.99,87.76 (B10).9
N$61
  Top 0.508: 22.99,165.1 22.99,172.72 (A14).5 | (A13).5 24.13,149.86 24.13,163.96 22.99,165.1 | 22.99,165.1 R79.2
  Bottom 0.508: 20.32,148.72 18.03,148.72 (A13).3 | (A13).6 25.27,148.72 22.99,148.72 (A13).5 22.61,148.72 20.32,148.72 | 20.32,148.72 (A13).4
N$62
  Top 0.508: (D9).1 138.43,62.23 (D9).12
N$63  (via drill 0.35)
  Top 0.508: v16.51,68.71 16.51,86.23 15.37,87.38 (A10).15
  Bottom 0.508: v16.51,68.71 16.51,59.56 15.37,58.42 (A9).1 | (B10).7 69.85,81.28 69.85,91.19 35.18,91.19 33.66,89.66 17.27,89.66 (A10).15
N$64  (via drill 0.35)
  Top 0.508: v133.48,91.95 133.48,87.76 (D10).14
  Bottom 0.508: v133.48,91.95 184.91,91.95 (E10).8
N$65  (via drill 0.35)
  Top 0.508: v181.48,208.53 181.48,223.39 (E16).5
  Bottom 0.508: v181.48,208.53 133.48,208.53 128.52,203.58 99.57,203.58 94.23,198.25 (C15).1
N$66  (via drill 0.35)
  Top 0.508: v134.62,200.91 134.62,217.3 140.72,223.39 (D16).5
  Bottom 0.508: v134.62,200.91 99.19,200.91 96.52,198.25 (C15).2
N$67  (via drill 0.35)
  Top 0.508: v142.24,73.66 142.24,86.23 141.1,87.38 (D10).11
  Bottom 0.508: v142.24,73.66 (D9).14
N$68  (via drill 0.35)
  Top 0.508: v219.58,42.42 219.58,56.9 (F9).3 | v122.05,62.61 v122.05,42.42
  Bottom 0.508: v122.05,42.42 v219.58,42.42 | v122.05,62.61 108.71,62.61 106.81,64.52 (C9).9
N$69
  Top 0.508: R49.1 99.19,72.14 101.47,69.85 101.47,64.9 (C9).11
  Bottom 0.508: 104.14,64.9 101.85,64.9 (C9).11 | (C9).8 107.19,66.8 106.05,66.8 104.14,64.9 | 104.14,64.9 (C9).10
N$71
  Bottom 0.508: 212.72,77.85 188.72,77.85 186.82,79.76 (E10).6 | 212.72,77.85 214.63,79.76 (F10).1 | (F9).2 218.44,58.42 218.44,77.47 213.11,77.47 212.72,77.85
N$72
  Top 0.508: (C15).10 104.14,221.11 101.85,223.39 (C16).5
N$73  (via drill 0.35)
  Top 0.508: v192.91,229.11 192.91,277.11 189.48,280.54 IC20.9 187.96,279.4 187.96,257.68 189.1,256.54 R61.1
  Bottom 0.508: v192.91,229.11 183.77,229.11 181.86,231.01 (E16).12
N$74  (via drill 0.35)
  Top 0.508: v166.62,223.77 167,224.16 167,253.87 v166.62,254.25 | IC20.4 179.2,272.92 179.2,256.54 R57.1
  Bottom 0.508: v166.62,223.77 171.2,223.77 (E16).1 | v166.62,254.25 176.53,254.25 178.82,256.54 R57.1
N$75  (via drill 0.35)
  Top 0.508: v165.86,253.11 v165.86,233.3 | IC20.5 181.86,272.92 181.86,256.54 R58.1
  Bottom 0.508: v165.86,233.3 171.96,233.3 173.86,231.39 (E16).15 | v165.86,253.11 178.05,253.11 181.48,256.54 R58.1
N$76
  Top 0.508: (C15).9 (C15).3
N$77  (via drill 0.35)
  Top 0.508: v194.06,255.02 v194.06,233.3 | R59.1 IC20.6
  Bottom 0.508: v194.06,233.3 178.44,233.3 176.53,231.39 (E16).14 | v194.06,255.02 185.67,255.02 R59.1
N$78
  Top 0.508: 186.82,256.54 190.63,252.73 190.63,245.87 183.01,238.25 183.01,235.2 179.2,231.39 (E16).13 | 186.82,256.54 186.82,272.92 IC20.7 | 186.82,256.54 R60.1
N$79  (via drill 0.35)
  Top 0.508: IC23.1 91.57,272.92 91.57,256.54 R70.1 | v83.57,256.54 v83.57,220.34
  Bottom 0.508: v83.57,220.34 95.76,220.34 98.81,223.39 (C16).4 | R70.1 v83.57,256.54
N$80  (via drill 0.35)
  Top 0.508: R62.1 IC22.1 | v125.86,219.2 125.86,223.01 126.24,223.39 126.24,254.25 125.86,254.64 v125.86,256.54
  Bottom 0.508: v125.86,219.2 134.24,219.2 138.43,223.39 (D16).4 | R62.1 v125.86,256.54
N$81  (via drill 0.35)
  Top 0.508: IC22.2 133.48,272.92 133.48,256.54 R63.1 | v122.05,258.06 v122.05,221.49
  Bottom 0.508: (D16).3 133.86,221.49 v122.05,221.49 | v122.05,258.06 131.57,258.06 133.1,256.54 R63.1
N$82  (via drill 0.35)
  Top 0.508: v141.1,244.73 141.1,231.39 (D16).12 | v153.29,244.73 152.91,245.11 152.91,256.54 | 152.91,256.54 152.91,274.83 148.72,279.02 148.72,280.54 IC22.9 | 152.91,256.54 v153.29,256.54
  Bottom 0.508: v153.29,244.73 v141.1,244.73 | v153.29,256.54 R69.1
N$83  (via drill 0.35)
  Top 0.508: v114.05,233.3 v114.05,256.54 114.81,257.3 114.81,280.54 109.47,280.54 IC23.9
  Bottom 0.508: (C16).12 103.76,233.3 v114.05,233.3 | R77.1 v114.05,256.54
N$84  (via drill 0.35)
  Top 0.508: IC20.1 171.58,272.92 171.58,256.54 R54.1 | v167.77,256.54 v167.77,220.34
  Bottom 0.508: v167.77,220.34 175.77,220.34 178.82,223.39 (E16).4 | R54.1 v167.77,256.54
N$85  (via drill 0.35)
  Top 0.508: IC20.2 174.24,272.92 174.24,256.54 R55.1 | v162.43,258.06 v162.43,221.49
  Bottom 0.508: v162.43,221.49 174.62,221.49 176.53,223.39 (E16).3 | v162.43,258.06 172.34,258.06 173.86,256.54 R55.1
N$86  (via drill 0.35)
  Top 0.508: v173.86,229.11 173.86,223.77 (E16).2 | v164.72,255.4 v164.72,229.11 | R56.1 IC20.3
  Bottom 0.508: v164.72,229.11 v173.86,229.11 | v164.72,255.4 170.43,255.4 170.81,255.02 175.01,255.02 R56.1
N$87  (via drill 0.35)
  Top 0.508: v133.1,220.34 133.1,223.39 (D16).2 | v127,255.02 v127,220.34 | IC22.3 136.14,272.92 136.14,256.54 R64.1
  Bottom 0.508: v127,220.34 v133.1,220.34 | v127,255.02 134.24,255.02 135.76,256.54 R64.1
N$88  (via drill 0.35)
  Top 0.508: v125.09,223.77 125.48,224.16 125.48,253.49 v124.71,254.25 | R65.1 IC22.4
  Bottom 0.508: v125.09,223.77 130.81,223.77 (D16).1 | v124.71,254.25 125.09,253.87 135.76,253.87 R65.1
N$89  (via drill 0.35)
  Top 0.508: v123.19,259.21 v123.19,229.49 | IC22.5 141.1,272.92 141.1,256.54 R66.1
  Bottom 0.508: v123.19,229.49 123.57,229.11 131.19,229.11 133.1,231.01 (D16).15 | v123.19,259.21 123.57,258.83 138.43,258.83 140.72,256.54 R66.1
N$90  (via drill 0.35)
  Top 0.508: v124.33,253.11 v124.33,233.3
  Bottom 0.508: v124.33,233.3 133.86,233.3 135.76,231.39 (D16).14 | v124.33,253.11 139.95,253.11 143.38,256.54 R67.1 143.76,256.54 143.76,272.92 IC22.6
N$91  (via drill 0.35)
  Top 0.508: v152.53,229.11 152.15,229.49 152.15,273.69 150.62,275.21 146.05,275.21 IC22.7 R68.1
  Bottom 0.508: v152.53,229.11 140.34,229.11 138.43,231.01 (D16).13
N$92  (via drill 0.35)
  Top 0.508: IC23.2 94.23,272.92 94.23,256.54 R71.1 | v87.76,255.02 v87.76,225.68
  Bottom 0.508: v87.76,225.68 94.62,225.68 96.52,223.77 (C16).3 | v87.76,255.02 92.33,255.02 93.85,256.54 R71.1
N$93  (via drill 0.35)
  Top 0.508: v82.42,258.06 v82.42,221.49 | R72.1 IC23.3
  Bottom 0.508: (C16).2 91.95,221.49 v82.42,221.49 | v82.42,258.06 95,258.06 R72.1
N$94  (via drill 0.35)
  Top 0.508: v84.71,223.77 84.33,224.16 84.33,255.78 84.71,256.16 v84.71,259.21 | IC23.4 99.19,272.92 99.19,256.54 R73.1
  Bottom 0.508: v84.71,223.77 91.19,223.77 (C16).1 | v84.71,259.21 85.09,258.83 96.52,258.83 98.81,256.54 R73.1
N$95  (via drill 0.35)
  Top 0.508: v86.61,253.87 v86.61,233.3 | IC23.5 101.85,272.92 101.85,256.54 R74.1
  Bottom 0.508: v86.61,233.3 91.95,233.3 93.85,231.39 (C16).15 | v86.61,253.87 98.81,253.87 101.47,256.54 R74.1
N$96  (via drill 0.35)
  Top 0.508: v85.47,252.73 v85.47,234.44 | R75.1 IC23.6
  Bottom 0.508: v85.47,234.44 93.47,234.44 96.52,231.39 (C16).14 | v85.47,252.73 100.33,252.73 R75.1
N$97
  Top 0.508: 106.81,256.54 110.62,252.73 110.62,242.82 99.19,231.39 (C16).13 | 106.81,256.54 106.81,272.92 IC23.7 | 106.81,256.54 R76.1
N$98  (via drill 0.35)
  Top 0.508: R88.1 IC31.1 | v7.75,256.54 v7.75,226.82
  Bottom 0.508: v7.75,226.82 17.27,226.82 20.32,223.77 (A16).4 | R88.1 v7.75,256.54
N$100  (via drill 0.35)
  Top 0.508: IC31.2 15.37,272.92 15.37,256.54 R89.1 | v8.89,255.02 v8.89,225.68
  Bottom 0.508: v8.89,225.68 15.75,225.68 17.65,223.77 (A16).3 | v8.89,255.02 13.46,255.02 14.99,256.54 R89.1
N$102
  Bottom 0.508: (E15).4 177.29,202.44 154.43,202.44 149.1,207.77 145.67,207.77 143.76,205.87 (D15).10
N$103  (via drill 0.35)
  Top 0.508: v13.84,242.06 16.51,239.4 16.51,224.92 15.37,223.77 (A16).2 | IC31.3 18.03,272.92 18.03,256.54 R90.1
  Bottom 0.508: v13.84,242.06 13.46,242.44 11.18,242.44 8.89,244.73 8.89,253.87 14.99,253.87 17.65,256.54 R90.1
N$104  (via drill 0.35)
  Top 0.508: v6.99,223.77 6.6,224.16 6.6,257.68 v6.99,258.06 | R91.1 IC31.4
  Bottom 0.508: v6.99,223.77 12.7,223.77 (A16).1 | v6.99,258.06 18.8,258.06 R91.1
N$105  (via drill 0.35)
  Top 0.508: v141.1,194.82 141.1,197.87 (D15).4
  Bottom 0.508: v141.1,194.82 141.48,195.2 173.86,195.2 176.53,197.87 (E15).2
N$106
  Top 0.508: IC31.5 22.99,272.92 22.99,256.54 R92.1
  Bottom 0.508: (A16).15 14.99,231.39 14.99,243.21 11.56,243.21 9.65,245.11 9.65,253.11 19.18,253.11 22.61,256.54 R92.1
N$107
  Bottom 0.508: (B11).1 32.51,126.24 32.51,128.91 27.18,128.91 22.99,133.1 (A12).12
N$108  (via drill 0.35)
  Top 0.508: v17.65,244.73 17.65,231.39 (A16).14 | v25.27,248.16 25.27,256.54 R93.1 25.65,256.54 25.65,272.92 IC31.6
  Bottom 0.508: v17.65,244.73 12.32,244.73 11.18,245.87 11.18,248.16 v25.27,248.16
N$109  (via drill 0.35)
  Top 0.508: v24.13,100.71 24.13,131.95 25.27,133.1 (A12).11
  Bottom 0.508: v24.13,100.71 56.52,100.71 58.42,102.62 (B11).2
N$110
  Top 0.508: R94.1 IC31.7
  Bottom 0.508: R94.1 23.75,252.35 10.41,252.35 10.41,245.49 11.94,243.97 15.75,243.97 15.75,235.97 20.32,231.39 (A16).13
N$111  (via drill 0.35)
  Top 0.508: v34.42,233.3 v34.42,256.54 34.42,274.07 33.27,274.07 v31.75,275.59
  Bottom 0.508: v34.42,233.3 24.89,233.3 22.99,231.39 (A16).12 | R95.1 v34.42,256.54 | IC31.9 31.75,279.4 v31.75,275.59
N$112  (via drill 0.35)
  Top 0.508: v22.99,112.52 22.99,125.48 (A12).5 | R97.2 22.99,95.38 22.99,102.62 (A11).5
  Bottom 0.508: 20.32,103 18.03,103 (A11).3 | 20.32,103 22.61,103 (A11).5 22.99,103 24.13,103 24.13,111.76 23.37,112.52 v22.99,112.52 | 20.32,103 (A11).4
N$113
  Top 0.508: (C14).4 101.85,172.72 102.62,171.96 102.62,157.86 104.14,156.34 (C13).10
N$115  (via drill 0.35)
  Top 0.508: (B12).3 61.09,125.48 61.47,125.09 61.47,119.76 62.61,118.62 62.61,112.14 62.23,111.76 62.23,106.81 66.04,103 (B11).5 | (B14).5 69.09,169.67 69.09,158.24 69.85,157.48 69.85,130.43 70.99,129.29 v70.99,128.91
  Bottom 0.508: v70.99,128.91 70.61,128.52 63.75,128.52 (B12).3
N$116  (via drill 0.35)
  Top 0.508: v207.01,68.71 207.01,58.8 v210.82,54.99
